VERSION 5.7 ;
  NOWIREEXTENSIONATPIN ON ;
  DIVIDERCHAR "/" ;
  BUSBITCHARS "[]" ;
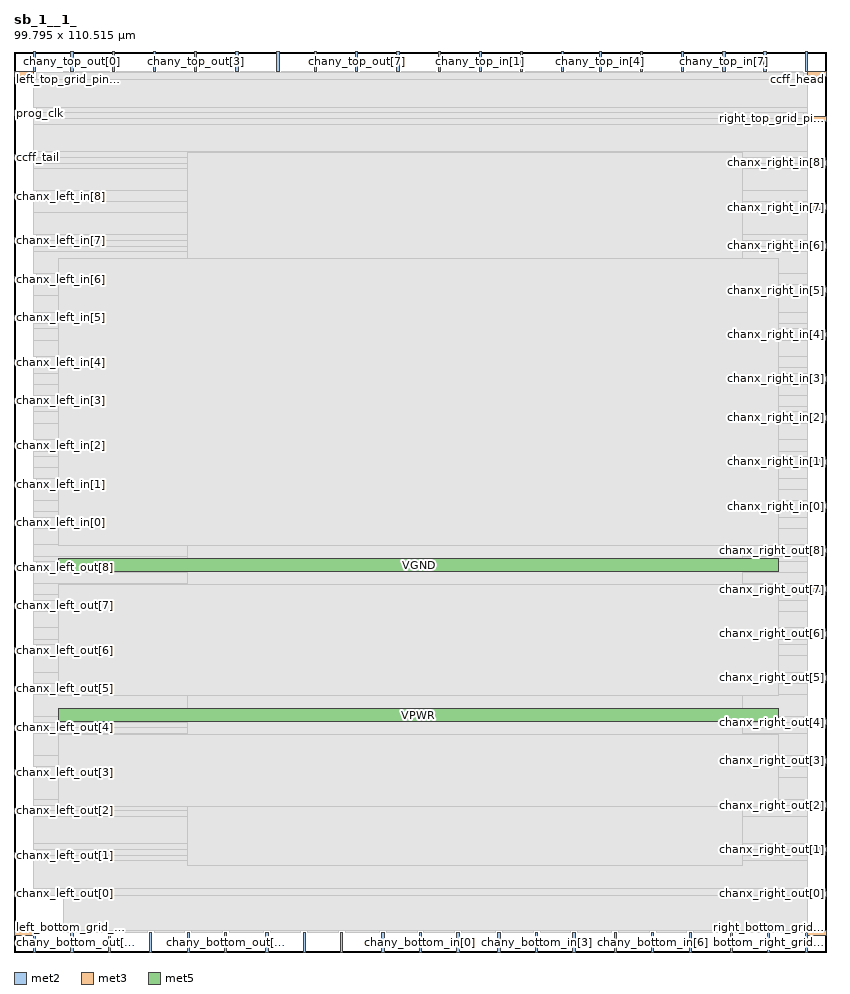
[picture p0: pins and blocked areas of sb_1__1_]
MACRO sb_1__1_
  CLASS BLOCK ;
  FOREIGN sb_1__1_ ;
  ORIGIN 0.000 0.000 ;
  SIZE 99.795 BY 110.515 ;
  PIN bottom_left_grid_pin_13_
    DIRECTION INPUT ;
    PORT
      LAYER met2 ;
        RECT 2.390 0.000 2.670 2.400 ;
    END
  END bottom_left_grid_pin_13_
  PIN bottom_right_grid_pin_11_
    DIRECTION INPUT ;
    PORT
      LAYER met2 ;
        RECT 92.550 0.000 92.830 2.400 ;
    END
  END bottom_right_grid_pin_11_
  PIN ccff_head
    DIRECTION INPUT ;
    PORT
      LAYER met3 ;
        RECT 97.395 107.480 99.795 108.080 ;
    END
  END ccff_head
  PIN ccff_tail
    DIRECTION OUTPUT TRISTATE ;
    PORT
      LAYER met3 ;
        RECT 0.000 97.280 2.400 97.880 ;
    END
  END ccff_tail
  PIN chanx_left_in[0]
    DIRECTION INPUT ;
    PORT
      LAYER met3 ;
        RECT 0.000 52.400 2.400 53.000 ;
    END
  END chanx_left_in[0]
  PIN chanx_left_in[1]
    DIRECTION INPUT ;
    PORT
      LAYER met3 ;
        RECT 0.000 57.160 2.400 57.760 ;
    END
  END chanx_left_in[1]
  PIN chanx_left_in[2]
    DIRECTION INPUT ;
    PORT
      LAYER met3 ;
        RECT 0.000 61.920 2.400 62.520 ;
    END
  END chanx_left_in[2]
  PIN chanx_left_in[3]
    DIRECTION INPUT ;
    PORT
      LAYER met3 ;
        RECT 0.000 67.360 2.400 67.960 ;
    END
  END chanx_left_in[3]
  PIN chanx_left_in[4]
    DIRECTION INPUT ;
    PORT
      LAYER met3 ;
        RECT 0.000 72.120 2.400 72.720 ;
    END
  END chanx_left_in[4]
  PIN chanx_left_in[5]
    DIRECTION INPUT ;
    PORT
      LAYER met3 ;
        RECT 0.000 77.560 2.400 78.160 ;
    END
  END chanx_left_in[5]
  PIN chanx_left_in[6]
    DIRECTION INPUT ;
    PORT
      LAYER met3 ;
        RECT 0.000 82.320 2.400 82.920 ;
    END
  END chanx_left_in[6]
  PIN chanx_left_in[7]
    DIRECTION INPUT ;
    PORT
      LAYER met3 ;
        RECT 0.000 87.080 2.400 87.680 ;
    END
  END chanx_left_in[7]
  PIN chanx_left_in[8]
    DIRECTION INPUT ;
    PORT
      LAYER met3 ;
        RECT 0.000 92.520 2.400 93.120 ;
    END
  END chanx_left_in[8]
  PIN chanx_left_out[0]
    DIRECTION OUTPUT TRISTATE ;
    PORT
      LAYER met3 ;
        RECT 0.000 6.840 2.400 7.440 ;
    END
  END chanx_left_out[0]
  PIN chanx_left_out[1]
    DIRECTION OUTPUT TRISTATE ;
    PORT
      LAYER met3 ;
        RECT 0.000 11.600 2.400 12.200 ;
    END
  END chanx_left_out[1]
  PIN chanx_left_out[2]
    DIRECTION OUTPUT TRISTATE ;
    PORT
      LAYER met3 ;
        RECT 0.000 17.040 2.400 17.640 ;
    END
  END chanx_left_out[2]
  PIN chanx_left_out[3]
    DIRECTION OUTPUT TRISTATE ;
    PORT
      LAYER met3 ;
        RECT 0.000 21.800 2.400 22.400 ;
    END
  END chanx_left_out[3]
  PIN chanx_left_out[4]
    DIRECTION OUTPUT TRISTATE ;
    PORT
      LAYER met3 ;
        RECT 0.000 27.240 2.400 27.840 ;
    END
  END chanx_left_out[4]
  PIN chanx_left_out[5]
    DIRECTION OUTPUT TRISTATE ;
    PORT
      LAYER met3 ;
        RECT 0.000 32.000 2.400 32.600 ;
    END
  END chanx_left_out[5]
  PIN chanx_left_out[6]
    DIRECTION OUTPUT TRISTATE ;
    PORT
      LAYER met3 ;
        RECT 0.000 36.760 2.400 37.360 ;
    END
  END chanx_left_out[6]
  PIN chanx_left_out[7]
    DIRECTION OUTPUT TRISTATE ;
    PORT
      LAYER met3 ;
        RECT 0.000 42.200 2.400 42.800 ;
    END
  END chanx_left_out[7]
  PIN chanx_left_out[8]
    DIRECTION OUTPUT TRISTATE ;
    PORT
      LAYER met3 ;
        RECT 0.000 46.960 2.400 47.560 ;
    END
  END chanx_left_out[8]
  PIN chanx_right_in[0]
    DIRECTION INPUT ;
    PORT
      LAYER met3 ;
        RECT 97.395 54.440 99.795 55.040 ;
    END
  END chanx_right_in[0]
  PIN chanx_right_in[1]
    DIRECTION INPUT ;
    PORT
      LAYER met3 ;
        RECT 97.395 59.880 99.795 60.480 ;
    END
  END chanx_right_in[1]
  PIN chanx_right_in[2]
    DIRECTION INPUT ;
    PORT
      LAYER met3 ;
        RECT 97.395 65.320 99.795 65.920 ;
    END
  END chanx_right_in[2]
  PIN chanx_right_in[3]
    DIRECTION INPUT ;
    PORT
      LAYER met3 ;
        RECT 97.395 70.080 99.795 70.680 ;
    END
  END chanx_right_in[3]
  PIN chanx_right_in[4]
    DIRECTION INPUT ;
    PORT
      LAYER met3 ;
        RECT 97.395 75.520 99.795 76.120 ;
    END
  END chanx_right_in[4]
  PIN chanx_right_in[5]
    DIRECTION INPUT ;
    PORT
      LAYER met3 ;
        RECT 97.395 80.960 99.795 81.560 ;
    END
  END chanx_right_in[5]
  PIN chanx_right_in[6]
    DIRECTION INPUT ;
    PORT
      LAYER met3 ;
        RECT 97.395 86.400 99.795 87.000 ;
    END
  END chanx_right_in[6]
  PIN chanx_right_in[7]
    DIRECTION INPUT ;
    PORT
      LAYER met3 ;
        RECT 97.395 91.160 99.795 91.760 ;
    END
  END chanx_right_in[7]
  PIN chanx_right_in[8]
    DIRECTION INPUT ;
    PORT
      LAYER met3 ;
        RECT 97.395 96.600 99.795 97.200 ;
    END
  END chanx_right_in[8]
  PIN chanx_right_out[0]
    DIRECTION OUTPUT TRISTATE ;
    PORT
      LAYER met3 ;
        RECT 97.395 6.840 99.795 7.440 ;
    END
  END chanx_right_out[0]
  PIN chanx_right_out[1]
    DIRECTION OUTPUT TRISTATE ;
    PORT
      LAYER met3 ;
        RECT 97.395 12.280 99.795 12.880 ;
    END
  END chanx_right_out[1]
  PIN chanx_right_out[2]
    DIRECTION OUTPUT TRISTATE ;
    PORT
      LAYER met3 ;
        RECT 97.395 17.720 99.795 18.320 ;
    END
  END chanx_right_out[2]
  PIN chanx_right_out[3]
    DIRECTION OUTPUT TRISTATE ;
    PORT
      LAYER met3 ;
        RECT 97.395 23.160 99.795 23.760 ;
    END
  END chanx_right_out[3]
  PIN chanx_right_out[4]
    DIRECTION OUTPUT TRISTATE ;
    PORT
      LAYER met3 ;
        RECT 97.395 27.920 99.795 28.520 ;
    END
  END chanx_right_out[4]
  PIN chanx_right_out[5]
    DIRECTION OUTPUT TRISTATE ;
    PORT
      LAYER met3 ;
        RECT 97.395 33.360 99.795 33.960 ;
    END
  END chanx_right_out[5]
  PIN chanx_right_out[6]
    DIRECTION OUTPUT TRISTATE ;
    PORT
      LAYER met3 ;
        RECT 97.395 38.800 99.795 39.400 ;
    END
  END chanx_right_out[6]
  PIN chanx_right_out[7]
    DIRECTION OUTPUT TRISTATE ;
    PORT
      LAYER met3 ;
        RECT 97.395 44.240 99.795 44.840 ;
    END
  END chanx_right_out[7]
  PIN chanx_right_out[8]
    DIRECTION OUTPUT TRISTATE ;
    PORT
      LAYER met3 ;
        RECT 97.395 49.000 99.795 49.600 ;
    END
  END chanx_right_out[8]
  PIN chany_bottom_in[0]
    DIRECTION INPUT ;
    PORT
      LAYER met2 ;
        RECT 49.770 0.000 50.050 2.400 ;
    END
  END chany_bottom_in[0]
  PIN chany_bottom_in[1]
    DIRECTION INPUT ;
    PORT
      LAYER met2 ;
        RECT 54.370 0.000 54.650 2.400 ;
    END
  END chany_bottom_in[1]
  PIN chany_bottom_in[2]
    DIRECTION INPUT ;
    PORT
      LAYER met2 ;
        RECT 59.430 0.000 59.710 2.400 ;
    END
  END chany_bottom_in[2]
  PIN chany_bottom_in[3]
    DIRECTION INPUT ;
    PORT
      LAYER met2 ;
        RECT 64.030 0.000 64.310 2.400 ;
    END
  END chany_bottom_in[3]
  PIN chany_bottom_in[4]
    DIRECTION INPUT ;
    PORT
      LAYER met2 ;
        RECT 68.630 0.000 68.910 2.400 ;
    END
  END chany_bottom_in[4]
  PIN chany_bottom_in[5]
    DIRECTION INPUT ;
    PORT
      LAYER met2 ;
        RECT 73.690 0.000 73.970 2.400 ;
    END
  END chany_bottom_in[5]
  PIN chany_bottom_in[6]
    DIRECTION INPUT ;
    PORT
      LAYER met2 ;
        RECT 78.290 0.000 78.570 2.400 ;
    END
  END chany_bottom_in[6]
  PIN chany_bottom_in[7]
    DIRECTION INPUT ;
    PORT
      LAYER met2 ;
        RECT 82.890 0.000 83.170 2.400 ;
    END
  END chany_bottom_in[7]
  PIN chany_bottom_in[8]
    DIRECTION INPUT ;
    PORT
      LAYER met2 ;
        RECT 87.950 0.000 88.230 2.400 ;
    END
  END chany_bottom_in[8]
  PIN chany_bottom_out[0]
    DIRECTION OUTPUT TRISTATE ;
    PORT
      LAYER met2 ;
        RECT 6.990 0.000 7.270 2.400 ;
    END
  END chany_bottom_out[0]
  PIN chany_bottom_out[1]
    DIRECTION OUTPUT TRISTATE ;
    PORT
      LAYER met2 ;
        RECT 11.590 0.000 11.870 2.400 ;
    END
  END chany_bottom_out[1]
  PIN chany_bottom_out[2]
    DIRECTION OUTPUT TRISTATE ;
    PORT
      LAYER met2 ;
        RECT 16.650 0.000 16.930 2.400 ;
    END
  END chany_bottom_out[2]
  PIN chany_bottom_out[3]
    DIRECTION OUTPUT TRISTATE ;
    PORT
      LAYER met2 ;
        RECT 21.250 0.000 21.530 2.400 ;
    END
  END chany_bottom_out[3]
  PIN chany_bottom_out[4]
    DIRECTION OUTPUT TRISTATE ;
    PORT
      LAYER met2 ;
        RECT 25.850 0.000 26.130 2.400 ;
    END
  END chany_bottom_out[4]
  PIN chany_bottom_out[5]
    DIRECTION OUTPUT TRISTATE ;
    PORT
      LAYER met2 ;
        RECT 30.910 0.000 31.190 2.400 ;
    END
  END chany_bottom_out[5]
  PIN chany_bottom_out[6]
    DIRECTION OUTPUT TRISTATE ;
    PORT
      LAYER met2 ;
        RECT 35.510 0.000 35.790 2.400 ;
    END
  END chany_bottom_out[6]
  PIN chany_bottom_out[7]
    DIRECTION OUTPUT TRISTATE ;
    PORT
      LAYER met2 ;
        RECT 40.110 0.000 40.390 2.400 ;
    END
  END chany_bottom_out[7]
  PIN chany_bottom_out[8]
    DIRECTION OUTPUT TRISTATE ;
    PORT
      LAYER met2 ;
        RECT 45.170 0.000 45.450 2.400 ;
    END
  END chany_bottom_out[8]
  PIN chany_top_in[0]
    DIRECTION INPUT ;
    PORT
      LAYER met2 ;
        RECT 52.070 108.115 52.350 110.515 ;
    END
  END chany_top_in[0]
  PIN chany_top_in[1]
    DIRECTION INPUT ;
    PORT
      LAYER met2 ;
        RECT 57.130 108.115 57.410 110.515 ;
    END
  END chany_top_in[1]
  PIN chany_top_in[2]
    DIRECTION INPUT ;
    PORT
      LAYER met2 ;
        RECT 62.190 108.115 62.470 110.515 ;
    END
  END chany_top_in[2]
  PIN chany_top_in[3]
    DIRECTION INPUT ;
    PORT
      LAYER met2 ;
        RECT 67.250 108.115 67.530 110.515 ;
    END
  END chany_top_in[3]
  PIN chany_top_in[4]
    DIRECTION INPUT ;
    PORT
      LAYER met2 ;
        RECT 71.850 108.115 72.130 110.515 ;
    END
  END chany_top_in[4]
  PIN chany_top_in[5]
    DIRECTION INPUT ;
    PORT
      LAYER met2 ;
        RECT 76.910 108.115 77.190 110.515 ;
    END
  END chany_top_in[5]
  PIN chany_top_in[6]
    DIRECTION INPUT ;
    PORT
      LAYER met2 ;
        RECT 81.970 108.115 82.250 110.515 ;
    END
  END chany_top_in[6]
  PIN chany_top_in[7]
    DIRECTION INPUT ;
    PORT
      LAYER met2 ;
        RECT 87.030 108.115 87.310 110.515 ;
    END
  END chany_top_in[7]
  PIN chany_top_in[8]
    DIRECTION INPUT ;
    PORT
      LAYER met2 ;
        RECT 92.090 108.115 92.370 110.515 ;
    END
  END chany_top_in[8]
  PIN chany_top_out[0]
    DIRECTION OUTPUT TRISTATE ;
    PORT
      LAYER met2 ;
        RECT 6.990 108.115 7.270 110.515 ;
    END
  END chany_top_out[0]
  PIN chany_top_out[1]
    DIRECTION OUTPUT TRISTATE ;
    PORT
      LAYER met2 ;
        RECT 12.050 108.115 12.330 110.515 ;
    END
  END chany_top_out[1]
  PIN chany_top_out[2]
    DIRECTION OUTPUT TRISTATE ;
    PORT
      LAYER met2 ;
        RECT 17.110 108.115 17.390 110.515 ;
    END
  END chany_top_out[2]
  PIN chany_top_out[3]
    DIRECTION OUTPUT TRISTATE ;
    PORT
      LAYER met2 ;
        RECT 22.170 108.115 22.450 110.515 ;
    END
  END chany_top_out[3]
  PIN chany_top_out[4]
    DIRECTION OUTPUT TRISTATE ;
    PORT
      LAYER met2 ;
        RECT 27.230 108.115 27.510 110.515 ;
    END
  END chany_top_out[4]
  PIN chany_top_out[5]
    DIRECTION OUTPUT TRISTATE ;
    PORT
      LAYER met2 ;
        RECT 32.290 108.115 32.570 110.515 ;
    END
  END chany_top_out[5]
  PIN chany_top_out[6]
    DIRECTION OUTPUT TRISTATE ;
    PORT
      LAYER met2 ;
        RECT 36.890 108.115 37.170 110.515 ;
    END
  END chany_top_out[6]
  PIN chany_top_out[7]
    DIRECTION OUTPUT TRISTATE ;
    PORT
      LAYER met2 ;
        RECT 41.950 108.115 42.230 110.515 ;
    END
  END chany_top_out[7]
  PIN chany_top_out[8]
    DIRECTION OUTPUT TRISTATE ;
    PORT
      LAYER met2 ;
        RECT 47.010 108.115 47.290 110.515 ;
    END
  END chany_top_out[8]
  PIN left_bottom_grid_pin_12_
    DIRECTION INPUT ;
    PORT
      LAYER met3 ;
        RECT 0.000 2.080 2.400 2.680 ;
    END
  END left_bottom_grid_pin_12_
  PIN left_top_grid_pin_10_
    DIRECTION INPUT ;
    PORT
      LAYER met3 ;
        RECT 0.000 107.480 2.400 108.080 ;
    END
  END left_top_grid_pin_10_
  PIN pReset
    DIRECTION INPUT ;
    PORT
      LAYER met2 ;
        RECT 97.150 0.000 97.430 2.400 ;
    END
  END pReset
  PIN prog_clk
    DIRECTION INPUT ;
    PORT
      LAYER met3 ;
        RECT 0.000 102.720 2.400 103.320 ;
    END
  END prog_clk
  PIN right_bottom_grid_pin_12_
    DIRECTION INPUT ;
    PORT
      LAYER met3 ;
        RECT 97.395 2.080 99.795 2.680 ;
    END
  END right_bottom_grid_pin_12_
  PIN right_top_grid_pin_10_
    DIRECTION INPUT ;
    PORT
      LAYER met3 ;
        RECT 97.395 102.040 99.795 102.640 ;
    END
  END right_top_grid_pin_10_
  PIN top_left_grid_pin_13_
    DIRECTION INPUT ;
    PORT
      LAYER met2 ;
        RECT 2.390 108.115 2.670 110.515 ;
    END
  END top_left_grid_pin_13_
  PIN top_right_grid_pin_11_
    DIRECTION INPUT ;
    PORT
      LAYER met2 ;
        RECT 97.150 108.115 97.430 110.515 ;
    END
  END top_right_grid_pin_11_
  PIN VPWR
    DIRECTION INPUT ;
    USE POWER ;
    PORT
      LAYER met5 ;
        RECT 5.520 28.260 93.840 29.860 ;
    END
  END VPWR
  PIN VGND
    DIRECTION INPUT ;
    USE GROUND ;
    PORT
      LAYER met5 ;
        RECT 5.520 46.680 93.840 48.280 ;
    END
  END VGND
  OBS
      LAYER li1 ;
        RECT 5.520 10.795 93.840 98.005 ;
      LAYER met1 ;
        RECT 5.520 10.640 97.450 101.280 ;
      LAYER met2 ;
        RECT 6.080 107.835 6.710 108.115 ;
        RECT 7.550 107.835 11.770 108.115 ;
        RECT 12.610 107.835 16.830 108.115 ;
        RECT 17.670 107.835 21.890 108.115 ;
        RECT 22.730 107.835 26.950 108.115 ;
        RECT 27.790 107.835 32.010 108.115 ;
        RECT 32.850 107.835 36.610 108.115 ;
        RECT 37.450 107.835 41.670 108.115 ;
        RECT 42.510 107.835 46.730 108.115 ;
        RECT 47.570 107.835 51.790 108.115 ;
        RECT 52.630 107.835 56.850 108.115 ;
        RECT 57.690 107.835 61.910 108.115 ;
        RECT 62.750 107.835 66.970 108.115 ;
        RECT 67.810 107.835 71.570 108.115 ;
        RECT 72.410 107.835 76.630 108.115 ;
        RECT 77.470 107.835 81.690 108.115 ;
        RECT 82.530 107.835 86.750 108.115 ;
        RECT 87.590 107.835 91.810 108.115 ;
        RECT 92.650 107.835 96.870 108.115 ;
        RECT 6.080 2.680 97.420 107.835 ;
        RECT 6.080 2.400 6.710 2.680 ;
        RECT 7.550 2.400 11.310 2.680 ;
        RECT 12.150 2.400 16.370 2.680 ;
        RECT 17.210 2.400 20.970 2.680 ;
        RECT 21.810 2.400 25.570 2.680 ;
        RECT 26.410 2.400 30.630 2.680 ;
        RECT 31.470 2.400 35.230 2.680 ;
        RECT 36.070 2.400 39.830 2.680 ;
        RECT 40.670 2.400 44.890 2.680 ;
        RECT 45.730 2.400 49.490 2.680 ;
        RECT 50.330 2.400 54.090 2.680 ;
        RECT 54.930 2.400 59.150 2.680 ;
        RECT 59.990 2.400 63.750 2.680 ;
        RECT 64.590 2.400 68.350 2.680 ;
        RECT 69.190 2.400 73.410 2.680 ;
        RECT 74.250 2.400 78.010 2.680 ;
        RECT 78.850 2.400 82.610 2.680 ;
        RECT 83.450 2.400 87.670 2.680 ;
        RECT 88.510 2.400 92.270 2.680 ;
        RECT 93.110 2.400 96.870 2.680 ;
      LAYER met3 ;
        RECT 2.800 107.080 96.995 107.945 ;
        RECT 2.400 103.720 97.395 107.080 ;
        RECT 2.800 103.040 97.395 103.720 ;
        RECT 2.800 102.320 96.995 103.040 ;
        RECT 2.400 101.640 96.995 102.320 ;
        RECT 2.400 98.280 97.395 101.640 ;
        RECT 2.800 97.600 97.395 98.280 ;
        RECT 2.800 96.880 96.995 97.600 ;
        RECT 2.400 96.200 96.995 96.880 ;
        RECT 2.400 93.520 97.395 96.200 ;
        RECT 2.800 92.160 97.395 93.520 ;
        RECT 2.800 92.120 96.995 92.160 ;
        RECT 2.400 90.760 96.995 92.120 ;
        RECT 2.400 88.080 97.395 90.760 ;
        RECT 2.800 87.400 97.395 88.080 ;
        RECT 2.800 86.680 96.995 87.400 ;
        RECT 2.400 86.000 96.995 86.680 ;
        RECT 2.400 83.320 97.395 86.000 ;
        RECT 2.800 81.960 97.395 83.320 ;
        RECT 2.800 81.920 96.995 81.960 ;
        RECT 2.400 80.560 96.995 81.920 ;
        RECT 2.400 78.560 97.395 80.560 ;
        RECT 2.800 77.160 97.395 78.560 ;
        RECT 2.400 76.520 97.395 77.160 ;
        RECT 2.400 75.120 96.995 76.520 ;
        RECT 2.400 73.120 97.395 75.120 ;
        RECT 2.800 71.720 97.395 73.120 ;
        RECT 2.400 71.080 97.395 71.720 ;
        RECT 2.400 69.680 96.995 71.080 ;
        RECT 2.400 68.360 97.395 69.680 ;
        RECT 2.800 66.960 97.395 68.360 ;
        RECT 2.400 66.320 97.395 66.960 ;
        RECT 2.400 64.920 96.995 66.320 ;
        RECT 2.400 62.920 97.395 64.920 ;
        RECT 2.800 61.520 97.395 62.920 ;
        RECT 2.400 60.880 97.395 61.520 ;
        RECT 2.400 59.480 96.995 60.880 ;
        RECT 2.400 58.160 97.395 59.480 ;
        RECT 2.800 56.760 97.395 58.160 ;
        RECT 2.400 55.440 97.395 56.760 ;
        RECT 2.400 54.040 96.995 55.440 ;
        RECT 2.400 53.400 97.395 54.040 ;
        RECT 2.800 52.000 97.395 53.400 ;
        RECT 2.400 50.000 97.395 52.000 ;
        RECT 2.400 48.600 96.995 50.000 ;
        RECT 2.400 47.960 97.395 48.600 ;
        RECT 2.800 46.560 97.395 47.960 ;
        RECT 2.400 45.240 97.395 46.560 ;
        RECT 2.400 43.840 96.995 45.240 ;
        RECT 2.400 43.200 97.395 43.840 ;
        RECT 2.800 41.800 97.395 43.200 ;
        RECT 2.400 39.800 97.395 41.800 ;
        RECT 2.400 38.400 96.995 39.800 ;
        RECT 2.400 37.760 97.395 38.400 ;
        RECT 2.800 36.360 97.395 37.760 ;
        RECT 2.400 34.360 97.395 36.360 ;
        RECT 2.400 33.000 96.995 34.360 ;
        RECT 2.800 32.960 96.995 33.000 ;
        RECT 2.800 31.600 97.395 32.960 ;
        RECT 2.400 28.920 97.395 31.600 ;
        RECT 2.400 28.240 96.995 28.920 ;
        RECT 2.800 27.520 96.995 28.240 ;
        RECT 2.800 26.840 97.395 27.520 ;
        RECT 2.400 24.160 97.395 26.840 ;
        RECT 2.400 22.800 96.995 24.160 ;
        RECT 2.800 22.760 96.995 22.800 ;
        RECT 2.800 21.400 97.395 22.760 ;
        RECT 2.400 18.720 97.395 21.400 ;
        RECT 2.400 18.040 96.995 18.720 ;
        RECT 2.800 17.320 96.995 18.040 ;
        RECT 2.800 16.640 97.395 17.320 ;
        RECT 2.400 13.280 97.395 16.640 ;
        RECT 2.400 12.600 96.995 13.280 ;
        RECT 2.800 11.880 96.995 12.600 ;
        RECT 2.800 11.200 97.395 11.880 ;
        RECT 2.400 7.840 97.395 11.200 ;
        RECT 2.800 6.975 96.995 7.840 ;
      LAYER met4 ;
        RECT 21.350 10.640 89.480 98.160 ;
      LAYER met5 ;
        RECT 5.520 49.880 93.840 85.115 ;
        RECT 5.520 31.460 93.840 45.080 ;
        RECT 5.520 17.900 93.840 26.660 ;
  END
END sb_1__1_
END LIBRARY

